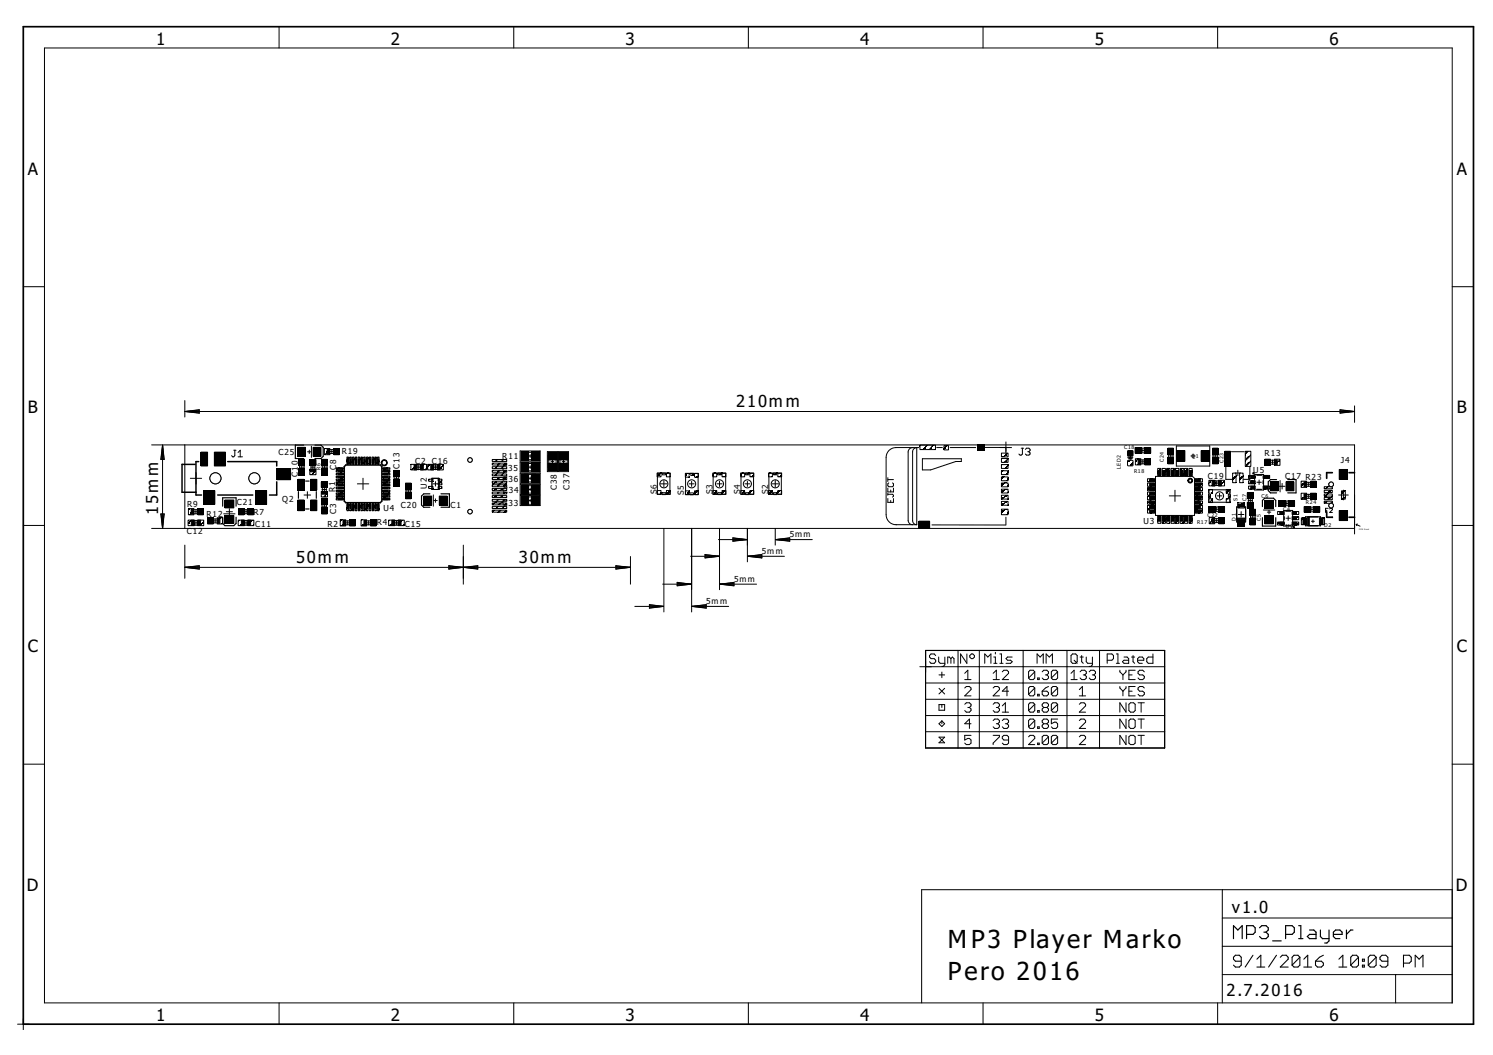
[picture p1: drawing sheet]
<svg xmlns="http://www.w3.org/2000/svg" width="297mm" height="210mm" viewBox="0 0 297 210" stroke-linecap="round" stroke-linejoin="round" font-family="sans-serif">
<defs><g id="words">
<g font-size="6">
<text x="188.6" y="188.6">MP3 Player Marko</text>
<text x="188.6" y="194.9">Pero 2016</text>
</g>
<g font-size="4.1">
<text x="31.1" y="8.9">1</text>
<text x="77.8" y="8.9">2</text>
<text x="124.4" y="8.9">3</text>
<text x="171.1" y="8.9">4</text>
<text x="217.8" y="8.9">5</text>
<text x="264.5" y="8.9">6</text>
<text x="5.5" y="34.7">A</text>
<text x="289.8" y="34.7">A</text>
<text x="5.5" y="82.2">B</text>
<text x="289.8" y="82.2">B</text>
<text x="5.5" y="129.7">C</text>
<text x="289.8" y="129.7">C</text>
<text x="5.4" y="177.2">D</text>
<text x="289.7" y="177.2">D</text>
<text x="31.1" y="203.1">1</text>
<text x="77.8" y="203.1">2</text>
<text x="124.4" y="203.1">3</text>
<text x="171.1" y="203.1">4</text>
<text x="217.8" y="203.1">5</text>
<text x="264.5" y="203.1">6</text>
</g>
<g font-size="4">
<text x="146.5" y="81">210mm</text>
<text x="31.5" y="102.4" transform="rotate(-90 31.5 102.4)">15mm</text>
<text x="58.9" y="112">50mm</text>
<text x="103.2" y="112">30mm</text>
<text x="245.1" y="181.6">v1.0</text>
<text x="244" y="198.2">2.7.2016</text>
</g>
<g font-size="2">
<text x="55.4" y="90.6">C25</text>
<text x="59.3" y="94.8" transform="rotate(-90 59.3 94.8)">C10</text>
<text x="66.8" y="93.6" transform="rotate(-90 66.8 93.6)">C8</text>
<text x="68" y="90.4">R19</text>
<text x="79.4" y="93.3" transform="rotate(-90 79.4 93.3)">C13</text>
<text x="82.6" y="92.2">C2 C16</text>
<text x="99.9" y="93.7">C35</text>
<text x="99.9" y="91.4">R11</text>
<text x="100" y="96">C36</text>
<text x="240.3" y="95.2">C19</text>
<text x="249.3" y="94">U5</text>
<text x="251.6" y="90.7">R13</text>
<text x="255.7" y="95.2">C17 R23</text>
<text x="266.8" y="92.1">J4</text>
<text x="37.2" y="100.9">R9</text>
<text x="47.1" y="100.5">C21</text>
<text x="56.1" y="99.9">Q2</text>
<text x="66.7" y="97.9" transform="rotate(-90 66.7 97.9)">R1</text>
<text x="76.3" y="101.6">U4</text>
<text x="79.7" y="101.1">C20</text>
<text x="84.9" y="97.3" transform="rotate(-90 84.9 97.3)">U2</text>
<text x="89.6" y="101.1">C1</text>
<text x="100" y="100.6">C33</text>
<text x="100" y="98.2">C34</text>
<text x="110.8" y="97.5" transform="rotate(-90 110.8 97.5)">C38</text>
<text x="113.3" y="97.4" transform="rotate(-90 113.3 97.4)">C37</text>
<text x="130.7" y="98.4" transform="rotate(-90 130.7 98.4)">S6</text>
<text x="136" y="98.6" transform="rotate(-90 136 98.6)">S5</text>
<text x="141.7" y="98.4" transform="rotate(-90 141.7 98.4)">S3</text>
<text x="147.3" y="98.4" transform="rotate(-90 147.3 98.4)">S4</text>
<text x="152.8" y="98.4" transform="rotate(-90 152.8 98.4)">S2</text>
<text x="37.2" y="106.3">C12</text>
<text x="41.1" y="102.9">R12</text>
<text x="50.4" y="102.5">R7</text>
<text x="50.7" y="104.8">C11</text>
<text x="65.2" y="104.8">R2</text>
<text x="66.9" y="102.2" transform="rotate(-90 66.9 102.2)">C3</text>
<text x="75" y="104.4">R4</text>
<text x="80.6" y="104.8">C15</text>
<text x="157.1" y="106.9">5mm</text>
<text x="227.5" y="104.3">U3</text>
<text x="151.6" y="110.2">5mm</text>
<text x="146" y="115.7">5mm</text>
<text x="140.5" y="120.2">5mm</text>
</g>
<g font-size="1.3">
<text x="223.7" y="89.4">C18</text>
<text x="63.8" y="93.6" transform="rotate(-90 63.8 93.6)">R6</text>
<text x="223" y="93.3" transform="rotate(-90 223 93.3)">LED2</text>
<text x="225.6" y="94.2">R18</text>
<text x="231.5" y="92" transform="rotate(-90 231.5 92)">C24</text>
<text x="237" y="91.1">Q1</text>
<text x="243.4" y="92.2" transform="rotate(-90 243.4 92.2)">C23</text>
<text x="246.2" y="99.6" transform="rotate(-90 246.2 99.6)">S1</text>
<text x="248" y="99.7" transform="rotate(-90 248 99.7)">C7</text>
<text x="251" y="99.1">C6</text>
<text x="255.3" y="101.7">C4</text>
<text x="259.8" y="100.4">R24</text>
<text x="238.2" y="104.3">R17</text>
<text x="240.3" y="102.8">C22</text>
<text x="245.9" y="103.6" transform="rotate(-90 245.9 103.6)">D1</text>
<text x="250.9" y="103.6" transform="rotate(-90 250.9 103.6)">C5</text>
<text x="255.8" y="105">U1</text>
<text x="263.4" y="104.8">D2</text>
</g>
<text font-size=".5" x="270.4" y="105.4">PCB Front</text>
</g></defs>
<g fill="#000" stroke="#000" stroke-width=".2">
<path d="M40 90h1.3v2.7h-1.3zM40.5 97.6h2.2v2.8h-2.2zM42.7 90h2.2v2.7h-2.2zM44.7 99.5h1.8v1.5h-1.8zM50.8 97.6h2.2v2.8h-2.2zM55.1 93.2h2.7v2.2h-2.7zM59.2 89h1.6v1.8h-1.6zM59.3 95.4h1.2v2.1h-1.2zM59.3 99.5h1.2v2.1h-1.2zM59.5 91.4h1.1v1.2h-1.1zM59.5 93.3h1.1v1.2h-1.1zM59.5 92h1.1v.6h-1.1z"/>
<path d="M59.5 93.3h1.1v.6h-1.1zM61.6 91.5h1.3v1.1h-1.3zM61.6 93.3h1.3v1.1h-1.3zM61.8 93.4h.9v.5h-.9zM61.8 92h.9v.5h-.9zM61.8 99.5h1.2v2.1h-1.2zM61.8 95.4h1.2v2.1h-1.2zM62.3 89h1.6v1.8h-1.6zM63.9 95.9h1.3v1.1h-1.3zM63.9 97.8h1.3v1.1h-1.3zM64 99.1h1.1v1.3h-1.1zM64 99.8h1v.5h-1z"/>
<path d="M64 91.4h1.1v1.2h-1.1zM64 93.3h1.1v1.2h-1.1zM64.1 92h1v.6h-1zM64.1 93.3h1v.6h-1zM64.1 97.9h.9v.4h-.9zM64.1 96.4h.9v.5h-.9zM64.5 89.2h1.1v1.3h-1.1zM65.1 89.4h.5v.9h-.5zM66.4 89.2h1.1v1.3h-1.1zM66.5 89.4h.5v.9h-.5zM66.9 93.1h1.3v.3h-1.3zM66.9 93.6h1.3v.3h-1.3z"/>
<path d="M66.9 94.2h1.3v.3h-1.3zM66.9 94.7h1.3v.3h-1.3zM66.9 95.3h1.3v.3h-1.3zM66.9 95.8h1.3v.3h-1.3zM66.9 96.4h1.3v.3h-1.3zM66.9 96.9h1.3v.3h-1.3zM66.9 97.5h1.3v.3h-1.3zM66.9 98.1h1.3v.3h-1.3zM66.9 98.6h1.3v.3h-1.3zM66.9 99.2h1.3v.3h-1.3zM67.2 93.1h1.2v.2h-1.2zM67.2 93.7h1.2v.2h-1.2z"/>
<path d="M67.2 94.2h1.2v.2h-1.2zM67.2 94.8h1.2v.2h-1.2zM67.2 95.3h1.2v.2h-1.2zM67.2 95.9h1.2v.2h-1.2zM67.2 96.4h1.2v.2h-1.2zM67.2 97h1.2v.2h-1.2zM67.2 97.6h1.2v.2h-1.2zM67.2 98.1h1.2v.2h-1.2zM67.2 98.7h1.2v.2h-1.2zM67.2 99.2h1.2v.2h-1.2zM69 90.9h.3v1.3h-.3zM69.1 91.3h.2v1.1h-.2z"/>
<path d="M69.6 90.9h.3v1.3h-.3zM69.6 91.3h.2v1.1h-.2zM70.1 90.9h.3v1.3h-.3zM70.2 91.3h.2v1.1h-.2zM70.7 90.9h.3v1.3h-.3zM70.7 91.3h.3v1.1h-.3zM71.2 90.9h.3v1.3h-.3zM71.3 91.3h.2v1.1h-.2zM71.8 90.9h.3v1.3h-.3zM71.8 91.3h.3v1.1h-.3zM72.4 90.9h.3v1.3h-.3zM72.4 91.3h.2v1.1h-.2z"/>
<path d="M72.9 90.9h.3v1.3h-.3zM73 91.3h.2v1.1h-.2zM73.5 90.9h.3v1.3h-.3zM73.5 91.3h.2v1.1h-.2zM74 90.9h.3v1.3h-.3zM74.1 91.3h.2v1.1h-.2zM74.6 90.9h.3v1.3h-.3zM74.6 91.3h.2v1.1h-.2zM75.1 90.9h.3v1.3h-.3zM75.2 91.3h.2v1.1h-.2zM76.1 99.2h1.1v.2h-1.1zM76.1 98.7h1.1v.2h-1.1z"/>
<path d="M76.1 98.1h1.1v.2h-1.1zM76.1 97.6h1.1v.2h-1.1zM76.1 97h1.1v.2h-1.1zM76.1 96.4h1.1v.2h-1.1zM76.1 95.9h1.1v.2h-1.1zM76.1 95.3h1.1v.2h-1.1zM76.1 94.8h1.1v.2h-1.1zM76.1 94.2h1.1v.2h-1.1zM76.1 93.7h1.1v.2h-1.1zM76.1 93.1h1.1v.2h-1.1zM76.3 99.2h1.3v.3h-1.3zM76.3 98.6h1.3v.3h-1.3z"/>
<path d="M76.3 98.1h1.3v.3h-1.3zM76.3 97.5h1.3v.3h-1.3zM76.3 96.9h1.3v.3h-1.3zM76.3 96.4h1.3v.3h-1.3zM76.3 95.8h1.3v.3h-1.3zM76.3 95.3h1.3v.3h-1.3zM76.3 94.7h1.3v.3h-1.3zM76.3 94.2h1.3v.3h-1.3zM76.3 93.6h1.3v.3h-1.3zM76.3 93.1h1.3v.3h-1.3zM78.3 95.5h1.1v1.2h-1.1zM78.3 93.6h1.1v1.2h-1.1z"/>
<path d="M78.3 95.5h1.1v.6h-1.1zM78.3 94.2h1.1v.6h-1.1zM80.7 96.1h1.1v1.2h-1.1zM80.7 98h1.1v1.2h-1.1zM80.7 96.8h1.1v.5h-1.1zM80.7 98h1.1v.6h-1.1zM81.7 92.4h1.3v1.1h-1.3zM82.4 92.4h.5v1.1h-.5zM83.6 92.4h1.3v1.1h-1.3zM83.7 92.4h.5v1.1h-.5zM84.3 98.7h1.6v1.8h-1.6zM85.1 92.4h1.2v1.1h-1.2z"/>
<path d="M85.3 96.8h.8v.4h-.8zM85.3 95.3h.8v.5h-.8zM85.7 92.4h.6v1.1h-.6zM87 92.4h1.2v1.1h-1.2zM87 92.4h.5v1.1h-.5zM87.2 96.8h.7v.4h-.7zM87.2 96.1h.7v.4h-.7zM87.2 95.3h.7v.4h-.7zM87.4 98.7h1.6v1.8h-1.6zM97.9 91.4h2.9v.4h-2.9zM97.9 92.1h2.9v.4h-2.9zM97.9 92.9h2.9v.3h-2.9z"/>
<path d="M97.9 93.6h2.9v.4h-2.9zM97.9 94.3h2.9v.4h-2.9zM97.9 95h2.9v.4h-2.9zM97.9 95.7h2.9v.4h-2.9zM97.9 96.5h2.9v.3h-2.9zM97.9 97.2h2.9v.4h-2.9zM97.9 97.9h2.9v.4h-2.9zM97.9 98.6h2.9v.4h-2.9zM97.9 99.4h2.9v.3h-2.9zM103.7 98.8h1.4v1.6h-1.4zM103.7 96.6h1.4v1.6h-1.4zM103.7 92.1h1.4v1.7h-1.4z"/>
<path d="M103.7 94.3h1.4v1.7h-1.4zM103.7 89.9h1.4v1.6h-1.4zM104.2 96.6h.9v1.6h-.9zM104.3 98.8h.8v1.6h-.8zM104.3 92.1h.8v1.6h-.8zM104.3 94.4h.8v1.6h-.8zM104.3 89.9h.8v1.6h-.8zM105.8 98.8h1.5v1.6h-1.5zM105.8 96.6h1.5v1.6h-1.5zM105.8 92.1h1.5v1.7h-1.5zM105.8 94.3h1.5v1.7h-1.5zM105.8 89.9h1.5v1.6h-1.5z"/>
<path d="M105.9 98.8h.8v1.6h-.8zM105.9 96.6h.8v1.6h-.8zM105.9 92.1h.8v1.6h-.8zM105.9 94.4h.8v1.6h-.8zM105.9 89.9h.8v1.6h-.8zM109.1 92.2h1.6v1.4h-1.6zM109.1 90.1h1.6v1.4h-1.6zM109.1 92.2h1.6v.8h-1.6zM109.1 90.6h1.6v.8h-1.6zM111.3 92.2h1.6v1.4h-1.6zM111.3 90.1h1.6v1.4h-1.6zM111.3 92.2h1.6v.8h-1.6z"/>
<path d="M111.3 90.6h1.6v.8h-1.6zM130.7 97.6h.8v.8h-.8zM130.7 94.1h.8v.8h-.8zM131.7 98h.8v.4h-.8zM131.7 94.1h.8v.4h-.8zM132.6 97.6h.7v.8h-.7zM132.6 94.1h.7v.8h-.7zM136.4 94.2h.7v.7h-.7zM136.4 97.7h.7v.7h-.7zM137.2 94.1h.8v.4h-.8zM137.2 98.1h.8v.3h-.8zM138.2 94.2h.7v.7h-.7z"/>
<path d="M138.2 97.7h.7v.7h-.7zM141.8 97.6h.8v.8h-.8zM141.8 94.1h.8v.8h-.8zM142.8 98h.7v.4h-.7zM142.8 94.1h.7v.4h-.7zM143.7 97.6h.7v.8h-.7zM143.7 94.1h.7v.8h-.7zM147.4 97.6h.7v.8h-.7zM147.4 94.1h.7v.8h-.7zM148.3 98h.8v.4h-.8zM148.3 94.1h.8v.4h-.8zM149.2 97.6h.8v.8h-.8z"/>
<path d="M149.2 94.1h.8v.8h-.8zM152.9 97.6h.8v.8h-.8zM152.9 94.1h.8v.8h-.8zM153.9 98h.7v.4h-.7zM153.9 94.1h.7v.4h-.7zM154.7 97.6h.8v.8h-.8zM154.7 94.1h.8v.8h-.8zM183 88.6h3.1v.9h-3.1zM187.8 88.7h.9v.8h-.9zM194.5 88.5h1.3v1.1h-1.3zM199.2 91.2h1.4v.8h-1.4zM199.2 92.4h1.4v.8h-1.4z"/>
<path d="M199.2 93.7h1.4v.7h-1.4zM199.2 94.9h1.4v.8h-1.4zM199.2 96.1h1.4v.8h-1.4zM199.2 97.3h1.4v.8h-1.4zM199.2 98.5h1.4v.8h-1.4zM199.2 99.8h1.4v.7h-1.4zM199.2 90.1h1.4v.8h-1.4zM225.8 89.1h1.3v1.1h-1.3zM225.9 91.3h1.1v1.2h-1.1zM226.4 91.4h.5v1h-.5zM226.5 89.1h.5v1h-.5zM227.7 89.1h1.2v1.1h-1.2z"/>
<path d="M227.8 89.1h.5v1h-.5zM227.8 91.3h1.1v1.2h-1.1zM227.9 91.4h.4v1h-.4zM228.3 95.2h1.4v.7h-1.4zM228.3 96.1h1.4v.7h-1.4zM228.3 97h1.4v.6h-1.4zM228.3 97.9h1.4v.6h-1.4zM228.3 98.8h1.4v.6h-1.4zM228.3 99.7h1.4v.6h-1.4zM228.7 95.3h1.1v.5h-1.1zM228.7 96.2h1.1v.5h-1.1zM228.7 97.1h1.1v.5h-1.1z"/>
<path d="M228.7 98h1.1v.5h-1.1zM228.7 98.8h1.1v.6h-1.1zM228.7 99.7h1.1v.5h-1.1zM230.3 93.2h.7v1.4h-.7zM230.4 93.6h.5v1.1h-.5zM231.2 93.2h.7v1.4h-.7zM231.3 93.6h.5v1.1h-.5zM232.1 93.2h.6v1.4h-.6zM232.2 93.6h.5v1.1h-.5zM232.4 89.2h1.1v1.2h-1.1zM232.4 91.1h1.1v1.2h-1.1zM232.4 89.8h1v.6h-1z"/>
<path d="M232.4 91.1h1v.6h-1zM233 93.2h.6v1.4h-.6zM233.1 93.6h.5v1.1h-.5zM233.9 93.2h.6v1.4h-.6zM234 93.6h.5v1.1h-.5zM234.1 89.7h1.6v2.1h-1.6zM234.8 93.2h.6v1.4h-.6zM234.8 93.6h.6v1.1h-.6zM235.7 93.2h.6v1.4h-.6zM235.7 93.6h.5v1.1h-.5zM236.6 93.2h.6v1.4h-.6zM236.6 93.6h.5v1.1h-.5z"/>
<path d="M237.7 99.7h1.1v.5h-1.1zM237.7 98.8h1.1v.6h-1.1zM237.7 98h1.1v.5h-1.1zM237.7 97.1h1.1v.5h-1.1zM237.7 96.2h1.1v.5h-1.1zM237.7 95.3h1.1v.5h-1.1zM237.8 99.7h1.4v.6h-1.4zM237.8 98.8h1.4v.6h-1.4zM237.8 97.9h1.4v.6h-1.4zM237.8 97h1.4v.6h-1.4zM237.8 96.1h1.4v.7h-1.4zM237.8 95.2h1.4v.7h-1.4z"/>
<path d="M239 89.7h1.6v2.1h-1.6zM240.5 98.3h.3v.7h-.3zM240.5 99.2h.7v.8h-.7zM240.5 97.4h.7v.7h-.7zM240.5 95.6h1.2v1.1h-1.2zM241.2 95.6h.5v1.1h-.5zM241.2 89.2h1.1v1.2h-1.1zM241.2 91.1h1.1v1.2h-1.1zM241.3 89.8h1v.6h-1zM241.3 91.1h1v.6h-1zM242.4 95.6h1.2v1.1h-1.2zM242.4 95.6h.6v1.1h-.6z"/>
<path d="M243.7 89.8h1.1v3h-1.1zM244 97.4h.7v.7h-.7zM244 99.2h.7v.8h-.7zM244.4 98.3h.4v.7h-.4zM245.2 94.1h.7v1.9h-.7zM246.6 94.1h.7v1.9h-.7zM247.8 89.8h1.1v3h-1.1zM248.2 99.9h1.1v1.2h-1.1zM248.2 98h1.1v1.2h-1.1zM248.3 98.7h.9v.4h-.9zM248.4 94.6h1.3v.6h-1.3zM248.4 95.7h1.3v.5h-1.3z"/>
<path d="M248.4 96.7h1.3v.6h-1.3zM248.9 94.6h.7v.6h-.7zM248.9 95.7h.7v.5h-.7zM248.9 96.7h.7v.6h-.7zM251.3 96.7h1.3v.6h-1.3zM251.3 94.6h1.3v.6h-1.3zM251.5 96.7h.7v.6h-.7zM251.5 94.6h.7v.6h-.7zM251.6 99.6h1.8v1.5h-1.8zM251.7 91.4h1.1v1.2h-1.1zM252.2 91.5h.5v1h-.5zM252.8 95.9h1.5v1.7h-1.5z"/>
<path d="M253.6 91.4h1.1v1.2h-1.1zM253.6 91.5h.5v1h-.5zM254.4 99.6h1.3v1.1h-1.3zM255.1 99.6h.5v1.1h-.5zM255.9 95.9h1.5v1.7h-1.5zM256.3 99.6h1.3v1.1h-1.3zM256.4 99.6h.5v1.1h-.5zM258.9 95.7h1.1v1.3h-1.1zM258.9 98.1h1.1v1.3h-1.1zM259.4 95.9h.5v.9h-.5zM259.4 98.3h.5v.9h-.5zM260.8 95.7h1.1v1.3h-1.1z"/>
<path d="M260.8 98.1h1.1v1.3h-1.1zM260.8 95.9h.5v.9h-.5zM260.8 98.3h.5v.9h-.5zM263.5 98.3h1.6v.4h-1.6zM263.5 99h1.6v.4h-1.6zM263.5 99.7h1.6v.4h-1.6zM263.5 97.6h1.6v.4h-1.6zM263.5 96.8h1.6v.5h-1.6zM266.4 93.4h1.7v2h-1.7zM266.9 97.7h.8v1.6h-.8zM37.4 103.5h1.3v1.1h-1.3zM37.5 101.2h1.1v1.2h-1.1z"/>
<path d="M38 101.3h.5v1h-.5zM38.1 103.5h.5v1h-.5zM39.3 103.5h1.2v1.1h-1.2zM39.3 103.5h.6v1h-.6zM39.4 101.2h1.1v1.2h-1.1zM39.5 101.3h.4v1h-.4zM41.3 103h1.1v1.2h-1.1zM41.9 103.1h.4v1h-.4zM43.2 103h1.1v1.2h-1.1zM43.3 103.1h.5v1h-.5zM44.7 102.6h1.8v1.5h-1.8zM47.4 103.5h1.2v1.1h-1.2z"/>
<path d="M47.5 101.2h1.1v1.2h-1.1zM48 103.5h.6v1h-.6zM48 101.3h.5v1h-.5zM49.3 103.5h1.2v1.1h-1.2zM49.3 103.5h.6v1h-.6zM49.3 101.2h1.1v1.2h-1.1zM49.4 101.3h.5v1h-.5zM64 101h1.1v1.3h-1.1zM64 101.1h1v.5h-1zM67.7 103.4h1.1v1.2h-1.1zM68.2 103.5h.5v1h-.5zM69 100.4h.3v1.2h-.3z"/>
<path d="M69.1 100.1h.2v1.1h-.2zM69.6 103.4h1.1v1.2h-1.1zM69.6 100.4h.3v1.2h-.3zM69.6 100.1h.2v1.1h-.2zM69.7 103.5h.4v1h-.4zM70.1 100.4h.3v1.2h-.3zM70.2 100.1h.2v1.1h-.2zM70.7 100.4h.3v1.2h-.3zM70.7 100.1h.3v1.1h-.3zM71.2 100.4h.3v1.2h-.3zM71.3 100.1h.2v1.1h-.2zM71.8 100.4h.3v1.2h-.3z"/>
<path d="M71.8 103.4h1.1v1.2h-1.1zM71.8 100.1h.3v1.1h-.3zM72.4 100.4h.3v1.2h-.3zM72.4 103.5h.5v1h-.5zM72.4 100.1h.2v1.1h-.2zM72.9 100.4h.3v1.2h-.3zM73 100.1h.2v1.1h-.2zM73.5 100.4h.3v1.2h-.3zM73.5 100.1h.2v1.1h-.2zM73.7 103.4h1.1v1.2h-1.1zM73.8 103.5h.5v1h-.5zM74 100.4h.3v1.2h-.3z"/>
<path d="M74.1 100.1h.2v1.1h-.2zM74.6 100.4h.3v1.2h-.3zM74.6 100.1h.2v1.1h-.2zM75.1 100.4h.3v1.2h-.3zM75.2 100.1h.2v1.1h-.2zM77.3 103.5h1.2v1.1h-1.2zM78 103.5h.5v1h-.5zM79.2 103.5h1.2v1.1h-1.2zM79.2 103.5h.6v1h-.6zM97.9 100.1h2.9v.4h-2.9zM97.9 100.8h2.9v.4h-2.9zM97.9 101.5h2.9v.4h-2.9z"/>
<path d="M182.8 103.7h2.2v1.4h-2.2zM199.2 101.3h1.4v1.1h-1.4zM228.3 100.6h1.4v.6h-1.4zM228.3 101.5h1.4v.6h-1.4zM228.7 100.6h1.1v.5h-1.1zM228.7 101.5h1.1v.5h-1.1zM230.3 102.7h.7v1.4h-.7zM230.4 102.6h.5v1.1h-.5zM231.2 102.7h.7v1.4h-.7zM231.3 102.6h.5v1.1h-.5zM232.1 102.7h.6v1.4h-.6zM232.2 102.6h.5v1.1h-.5z"/>
<path d="M233 102.7h.6v1.4h-.6zM233.1 102.6h.5v1.1h-.5zM233.9 102.7h.6v1.4h-.6zM234 102.6h.5v1.1h-.5zM234.8 102.7h.6v1.4h-.6zM234.8 102.6h.6v1.1h-.6zM235.7 102.7h.6v1.4h-.6zM235.7 102.6h.5v1.1h-.5zM236.6 102.7h.6v1.4h-.6zM236.6 102.6h.5v1.1h-.5zM237.7 101.5h1.1v.5h-1.1zM237.7 100.6h1.1v.5h-1.1z"/>
<path d="M237.8 101.5h1.4v.6h-1.4zM237.8 100.6h1.4v.6h-1.4zM240.5 100.8h1.2v1.1h-1.2zM240.6 103h1.1v1.2h-1.1zM241.1 103.1h.5v1h-.5zM241.2 100.8h.5v1.1h-.5zM242.4 100.8h1.2v1.1h-1.2zM242.4 100.8h.6v1.1h-.6zM242.5 103h1.1v1.2h-1.1zM242.5 103.1h.5v1h-.5zM246 103.1h1.8v.3h-1.8zM246.3 100.1h1.3v1h-1.3z"/>
<path d="M246.3 103.7h1.3v1h-1.3zM246.3 103.9h1.2v.5h-1.2zM246.3 100.4h1.2v.4h-1.2zM248.3 100.1h.9v.3h-.9zM248.7 101.3h1.1v1.3h-1.1zM248.7 103.2h1.1v1.2h-1.1zM248.7 102h1.1v.5h-1.1zM248.7 103.3h1.1v.5h-1.1zM251.6 102.7h1.8v1.5h-1.8zM254.2 101.8h1.3v.6h-1.3zM254.2 103.9h1.3v.6h-1.3zM254.6 101.8h.7v.5h-.7z"/>
<path d="M254.6 103.9h.7v.5h-.7zM257.1 103.9h1.3v.6h-1.3zM257.1 102.8h1.3v.6h-1.3zM257.1 101.8h1.3v.6h-1.3zM257.2 103.9h.7v.5h-.7zM257.2 102.8h.7v.6h-.7zM257.2 101.8h.7v.5h-.7zM258.9 103h1v1.4h-1zM259.2 103.1h.5v1.2h-.5zM259.5 100.8h1.2v1.1h-1.2zM260.1 100.8h.5v1.1h-.5zM260.2 102.8h.3v1.8h-.3z"/>
<path d="M261.3 100.8h1.3v1.1h-1.3zM261.4 100.8h.5v1.1h-.5zM262.5 103h1v1.4h-1zM262.8 103.1h.4v1.2h-.4zM266.4 101.6h1.7v2h-1.7z"/>
</g>
<g fill="#000" stroke="#000" stroke-width=".2">
<path d="M76 91.7a.61 .61 0 0 1 1 .1 .61 .61 0 0 1-.4 .9 .61 .61 0 0 1-.8-.6h.2a.47 .47 0 0 1 .7-.4 .47 .47 0 0 1 .1 .8 .47 .47 0 0 1-.8-.3v-.1h-.2z" fill-rule="evenodd"/>
<path d="M224.4 89.7h1v1h-1z" fill-rule="evenodd"/>
<path d="M224.4 91.6h1v1h-1z" fill-rule="evenodd"/>
<path d="M236.5 95.2a.48 .48 0 0 1 .7 .2 .48 .48 0 0 1-.3 .7 .48 .48 0 0 1-.6-.5h.2a.32 .32 0 0 1 .4-.2 .32 .32 0 0 1 .1 .5 .32 .32 0 0 1-.5-.1l-.2-.2z" fill-rule="evenodd"/>
<circle cx="249.4" cy="94.2" r=".15"/>
<circle cx="257.4" cy="104.9" r=".15"/>
</g>
<g fill="none" stroke="#000" stroke-width=".23">
<path d="M59.4 97.8v1.3M60.4 88.6h-1.6v2.6h1.6M60.8 95.7h.7M62.7 88.6h1.2l.4 .4v1.8l-.4 .4h-1.2M62.9 97.8v1.3M85.5 98.3h-1.2l-.4 .4v1.8l.4 .4h1.2M87.7 98.3h1.7v2.6h-1.7M224.4 91h1M224.6 91.3l.3-.3 .2 .3M250 97.4h1M250 94.6h1M251.3 95.7v.5"/>
<path d="M254 95.4h-1.2l-.5 .5v1.7l.5 .5h1.2M256.2 95.4h1.7v2.7h-1.7M44.3 102.9v1.2l.4 .5h1.8l.5-.5v-1.2M44.3 100.7v-1.7h2.7v1.7M60.8 101.3h.7M246 100.9h1.8v2.9h-1.8zM251.2 100.8v-1.2l.4-.5h1.8l.4 .5v1.2M251.2 103v1.7h2.6v-1.7M255.5 102.8v.6M255.8 101.7h1M255.8 104.5h1M259.7 102.8h3v1.8h-3z"/>
</g>
<g fill="none" stroke="#000" stroke-width=".2">
<path d="M36.8 79.7v3.3M30.2 88.5h239.3v17.7M32.3 88.6v16.5M32.3 88.6l.4 2.8h-.7zM32.3 88.6l-.1 2.8M32.3 88.6l.2 2.8M32.3 88.6l-.3 2.8M32.3 88.6l.3 2.8M36.8 88.5v16.6M36.8 81.9h232.6M36.8 81.9l2.8-.4v.7zM36.8 81.9l2.8 .1"/>
<path d="M36.8 81.9l2.8 .2M37.9 95.2h2.2M39 94v2.3M39.6 81.7l-2.8 .2M39.6 81.6l-2.8 .3M46.5 89.6h.4M46.7 89.6v1.1l-.2 .2h-.2l-.2-.2M47.4 90.9h.8M47.4 90l.4-.4v1.3M59.6 92.5v.8M59.6 92.9h.8M60 92.6v.7"/>
<path d="M60.5 98.5h1.3M60.5 92.5v.8M61.2 97.8v1.3M61.2 89.9h.7M61.5 89.6v.7M61.9 92.5v.9M61.9 92.9h.7M62 88.8v2.2M62.3 92.6v.7M62.7 92.5v.9M64.1 97.4h.9M64.1 92.9h1"/>
<path d="M64.1 92.5v.8M64.1 96.9v1M64.5 96.9v1M64.6 92.4v1.1M64.9 96.9v1M65.1 92.5v.8M65.6 90.2h.9M65.6 89.5h.9M65.6 89.9h.8M66 89.5v.7M71.1 96.3h2.3M72.2 95.1v2.3"/>
<path d="M78.4 94.8v.7M78.5 95.2h.8M78.9 94.8v.8M79.3 94.8v.7M80.7 97.7h1M80.8 97.3v.8M81.2 97.2v1M81.7 97.3v.8M82.8 92.9h1M82.9 92.5h.8M82.9 93.4h.8M83.3 92.4v1.1"/>
<path d="M85.9 95.2h1.4v2.2h-1.4zM86.1 92.9h1.1M86.2 96.3h.9M86.2 98.5v2.2M86.2 92.5h.8M86.2 93.4h.8M86.3 99.6h.7M86.6 92.4v1.1M86.6 95.8v.9M86.6 99.3v.6M103.5 89.7h4v2h-4zM103.5 91.9h4v2h-4z"/>
<path d="M103.5 94.2h4v2h-4zM103.5 96.4h4v2h-4zM103.5 98.6h4v2h-4zM105.1 94.4h.8M105.1 98.9h.8M105.1 98.1h.8M105.1 96.6h.8M105.1 92.2h.8M105.1 90h.8M105.1 93.7h.8M105.1 95.9h.8M105.1 91.5h.8"/>
<path d="M105.2 95.2h.5M105.2 97.4h.5M105.2 99.6h.5M105.2 92.9h.5M105.2 90.7h.5M105.5 90.4v.6M105.5 92.7v.5M105.5 94.9v.5M105.5 97.1v.6M105.5 99.3v.6M108.9 89.9h2v3.9h-2zM109.2 91.4v.9"/>
<path d="M109.6 91.8h.6M109.9 91.5v.6M110.6 91.4v.8M111.1 89.9h2v3.9h-2zM111.4 91.4v.9M111.8 91.8h.6M112.1 91.5v.6M112.9 91.4v.8M130.8 94.2h2.5v4.1h-2.5zM131.4 96.3h1.3M132.1 95.6v1.3M136.4 94.2h2.5v4.2h-2.5z"/>
<path d="M137.1 96.3h1M137.6 95.8v1M141.9 94.2h2.5v4.1h-2.5zM142.6 96.3h1.1M143.2 95.7v1.1M147.4 94.2h2.5v4.1h-2.5zM148.2 96.3h1M148.7 95.8v1M153 94.2h2.4v4.1h-2.4zM153.6 96.3h1.3M154.2 95.6v1.3M176.6 95.4h1.2"/>
<path d="M176.6 99.2v.7h1.2v-.7M176.6 98.3h1l.2 .2-.2 .4M176.6 95v.8M176.6 97.1v.8h1.2v-.8M176.6 98.1v.4M176.8 96.1l-.2 .2v.3l.2 .2h.8l.2-.2v-.3l-.2-.2M177.2 97.5v.4M177.2 99.6v.3M181.6 89l-.7 .3-.2 .6v13.6l.2 .6 .7 .3M181.8 89.3l.6-.3v15.4l-.6-.2-.2-.6v-13.7zM182.8 89h-4.6a1.95 1.95 0 0 0-1.9 2v11.4a1.99 1.99 0 0 0 2 2h4.1M183.5 91.3h7.8v.5h-1.1l-5 1.7h-1.7z"/>
<path d="M186.4 89h1.1M189 89h5.1M196 89h5.3M200.1 87.9v2.3M203.2 89.2h.4M203.4 89.2v1.1l-.2 .3-.5-.3M204 89.4l.2-.2h.5l.2 .2v.2l-.2 .3M204.5 89.9h.2M204.7 89.9l.2 .2v.2l-.2 .3h-.5l-.2-.3M224.5 91.2h.8M224.9 90.7v.9M226.9 92.3h1"/>
<path d="M226.9 91.5h1M227 90.1h.8M227 89.2h.8M227 89.6h.8M227 91.9h.8M227.4 89.2v.8M227.4 91.5v.8M229.9 94.8h7.4l.4 .4v7.4h-7.8zM232.5 90.3v.8M232.5 90.7h.8M232.6 98.7h2.3M232.9 90.3v.8"/>
<path d="M233.4 90.3v.8M233.8 97.5v2.3M234 88.7h6.7v4h-6.7zM236.9 90.7h.9M237.4 90.3v.8M240.5 97.5h4.2v2.4h-4.2zM241.3 90.3v.8M241.3 90.7h1M241.7 96.6h.8M241.7 95.7h.8M241.7 96.1h.8M241.8 90.3v.9"/>
<path d="M242.1 95.7v.8M242.1 98.7h1M242.3 90.3v.8M242.6 98.2v.9M243.9 92.8v2.6h1.3M245 89.9h2.5M245.7 94.1h1.1M246.3 93.6v1M248.3 99.6h.9M248.4 98.8v1.6M248.7 92.8v2.6h-1.3M248.8 99.1v.9"/>
<path d="M249.2 98.8v1.6M249.6 94.4h1.8v3.1h-1.8zM250.1 95.9h.9M250.5 95.5v.9M252.7 91.6h.9M252.7 92.4h.9M252.7 92h.9M253.2 91.5v.9M254.5 96.8h1.2M254.7 95.6v2.3M255.1 96.2v1.1M255.6 99.7h.8"/>
<path d="M256 99.8v.7M259.9 98.4h.9M259.9 96h.9M259.9 96.8h.9M259.9 99.1h.9M259.9 98.7h.9M260 96.4h.8M260.4 95.9v.9M260.4 98.3v.9M266.3 98.5h1.9M266.6 81.5l2.8 .4-2.8 .3zM266.6 81.7l2.8 .2"/>
<path d="M266.6 81.6l2.8 .3M267.3 97.5v2M269.4 81.9l-2.8 .1M269.4 81.9l-2.8 .2M269.5 80.8v3.2M30.2 105.1h239.3M32 102.3h.7l-.4 2.8zM32 102.3l.3 2.8M32.2 102.3l.1 2.8M32.5 102.3l-.2 2.8M32.6 102.3l-.3 2.8M36.8 108.5v6.6"/>
<path d="M36.8 112.9l2.8-.4v.7zM36.8 112.9h55.3M36.8 112.9l2.8 .1M36.8 112.9l2.8 .3M38.5 102.2h1M38.5 101.4h1M38.6 101.8h.8M38.6 103.5h.8M38.6 104.5h.8M38.6 104h.8M39 101.4v.8M39 103.6v.8"/>
<path d="M39.6 112.8l-2.8 .1M39.6 112.6l-2.8 .3M42.3 103.3h1M42.3 104h1M42.4 103.6h.8M42.8 103.3v.7M44.5 102.2h2.3M45 101.8h1.2M45.6 101.2v1.2M48.5 102.2h.9M48.5 101.4h.9M48.6 103.5h.8"/>
<path d="M48.6 104.5h.8M48.6 101.8h.7M48.6 104h.7M49 101.4v.8M49 103.7v.7M64.1 100.3v.8M64.1 100.7h.8M64.5 100.3v.8M65 100.3v.8M68.7 104.4h1M68.7 103.6h1M68.8 104h.8"/>
<path d="M69.2 103.7v.7M72.9 104.4h.9M72.9 103.6h.9M72.9 104h.9M73.3 103.6v.8M78.5 103.5h.8M78.5 104.5h.8M78.5 104h.8M78.9 103.7v.7M89.3 112.5l2.8 .4-2.8 .3zM89.3 112.8l2.8 .1M89.3 112.6l2.8 .3"/>
<path d="M92.1 112.9l-2.8 .1M92.1 112.9l-2.8 .3M92.2 108.5v7.7M92.2 112.9h33.1M92.2 112.9l2.9-.4v.7zM92.2 112.9l2.9 .1M92.2 112.9l2.9 .3M95.1 112.6l-2.9 .3M95.1 112.8l-2.9 .1M105.1 100.3h.8M122.5 112.5l2.8 .4-2.8 .3zM122.5 112.8l2.8 .1"/>
<path d="M122.5 112.6l2.8 .3M125.3 112.9l-2.8 .1M125.3 112.9l-2.8 .3M125.4 110.7v5.5M131.8 116.2h5.7M132.1 105.1v16.7M134.7 115.9l2.8 .3-2.8 .4zM134.7 116.1l2.8 .1M134.7 115.9l2.8 .3M137.4 110.7h5.7M137.5 116.2l-2.8 .2M137.5 116.2l-2.8 .3"/>
<path d="M137.6 105.1v16.7M140.3 110.3l2.8 .4-2.8 .3zM140.3 110.5l2.8 .2M140.3 110.4l2.8 .3M142.9 107.4h5.7M143.1 110.7l-2.8 .1M143.1 110.7l-2.8 .3M143.2 105.1v12.2M143.2 116.2h7.3M143.2 116.2l2.8-.3v.7zM143.2 116.2l2.8 .2M143.2 116.2l2.8 .3"/>
<path d="M145.8 107l2.8 .4-2.8 .3zM145.8 107.2l2.8 .2M145.8 107.1l2.8 .3M146 116.1l-2.8 .1M146 115.9l-2.8 .3M148.6 107.4l-2.8 .1M148.6 107.4l-2.8 .2M148.7 105.1v6.7M148.8 110.7h7.3M148.8 110.7l2.8-.4v.7zM148.8 110.7l2.8 .1M148.8 110.7l2.8 .3"/>
<path d="M151.6 110.5l-2.8 .2M151.6 110.4l-2.8 .3M154.2 105.1v3.4M154.3 107.4h7.3M154.3 107.4l2.8-.4v.7zM154.3 107.4l2.8 .1M154.3 107.4l2.8 .2M157.1 107.2l-2.8 .2M157.1 107.1l-2.8 .3M185.4 104.4l14.7 .1M200.1 102.9v1.5M241.6 103.2h.9"/>
<path d="M241.6 104h.9M241.7 100.9h.8M241.7 101.8h.8M241.7 103.6h.7M241.7 101.3h.7M242.1 101v.7M242.1 103.2v.8M246.4 102.4h1.1M246.9 101.8v1.1M248.8 102.5v.8M248.8 102.9h.9M249.2 102.4v.9"/>
<path d="M249.7 102.5v.8M251.4 101.5h2.2M252.1 101.9h.7M252.5 101.5v.8M255.4 101.6h1.8v3.1h-1.8zM255.6 100.6h.8M255.6 100.2h.8M255.8 103.1h.9M256.3 102.7v.8M260.6 101.8h.8M260.6 100.9h.8M260.7 101.3h.6"/>
<path d="M260.9 103.7h.6M261 101.1v.5M261.2 103.4v.6M263.7 101.5h.3M264.2 101.1h-.5v.9M264.5 101.3l.2-.2 .4 .2-.6 .7h.6M269.8 104.4l.8 .3M269.8 104.4l.1 .2M270 104.2l-.2 .2M126.3 120.6h5.7M129.2 120.3l2.8 .3-2.8 .4zM129.2 120.5l2.8 .1"/>
<path d="M129.2 120.4l2.8 .2M132 120.6l-2.8 .2M132 120.6l-2.8 .3M137.7 120.6h7.3M137.7 120.6l2.8-.3v.7zM137.7 120.6l2.8 .2M137.7 120.6l2.8 .3M140.5 120.5l-2.8 .1M140.5 120.4l-2.8 .2M183 132.7h2.3M184.1 131.5v2.3M3.5 203.8h2.3"/>
<path d="M4.6 202.6v2.3"/>
<circle cx="42.9" cy="95.2" r="1.1"/>
<circle cx="132.1" cy="96.3" r=".8"/>
<circle cx="137.6" cy="96.3" r=".8"/>
<circle cx="143.2" cy="96.3" r=".8"/>
<circle cx="148.7" cy="96.3" r=".8"/>
<circle cx="154.2" cy="96.3" r=".8"/>
<circle cx="242.6" cy="98.7" r=".8"/>
</g>
<path d="M38.8 92.4h-2.6v5.5h2.8M39.5 91.8h-.5v6.7h1.1M43.3 98.5h7M45.3 91.8h9.8v.9M55.1 95.9v2.6h-1.5M68.8 92.5h6.9l.3 .3v6.9l-.3 .3h-6.9l-.3-.3v-6.9z" fill="none" stroke="#000" stroke-width=".3"/>
<path d="M265.1 94h-1.2v1.2M268.4 94h1.1M263.9 101.8l.1 1.1h1.1M265.1 102.9h.1M268.4 102.9h1.1" fill="none" stroke="#000" stroke-width=".34"/>
<circle cx="42.9" cy="95.2" r="1.1" fill="#fff" stroke="#000" stroke-width=".2"/>
<circle cx="50.6" cy="95.2" r="1.1" fill="none" stroke="#000" stroke-width=".2"/>
<circle cx="50.6" cy="95.2" r="1.1" fill="#fff" stroke="#000" stroke-width=".2"/>
<circle cx="93.5" cy="91.5" r=".44" fill="none" stroke="#000" stroke-width=".2"/>
<circle cx="93.5" cy="91.5" r=".44" fill="#fff" stroke="#000" stroke-width=".2"/>
<circle cx="93.5" cy="101.8" r=".44" fill="none" stroke="#000" stroke-width=".2"/>
<circle cx="93.5" cy="101.8" r=".44" fill="#fff" stroke="#000" stroke-width=".2"/>
<circle cx="264.8" cy="100.6" r=".47" fill="none" stroke="#000" stroke-width=".2"/>
<circle cx="264.8" cy="100.6" r=".47" fill="#fff" stroke="#000" stroke-width=".2"/>
<circle cx="264.8" cy="96.4" r=".47" fill="none" stroke="#000" stroke-width=".2"/>
<circle cx="264.8" cy="96.4" r=".47" fill="#fff" stroke="#000" stroke-width=".2"/>
<g fill="none" stroke="#000" stroke-width=".2">
<path d="M8.8 9.5h280.1v190h-280.1zM55.5 5.3v4.2M102.2 5.3v4.2M148.9 5.3v4.2M195.6 5.3v4.2M242.3 5.3v4.2M4.6 57h4.2M288.9 57h4.3M4.6 104.5h4.2M288.9 104.5h4.3M184.1 129.4v3.3h47.6M184.1 135.9h47.6"/>
<path d="M184.1 139.1h47.6M186.2 130.4l-.3-.3h-.7l-.3 .3v.3l.3 .3h.7l.3 .4v.3l-.3 .3h-.7l-.3-.3M186.8 130.7v1l.2 .3h1M186.8 134.3h1.1M186.8 136.9l1.1 1.2M187.4 133.7v1.1M187.9 136.9l-1.1 1.2M188 130.7v1.6l-.3 .3h-.3M189.2 131l-.3-.3h-.3v1.3M189.2 131v1M189.2 131l.3-.3 .3 .3v1M190.6 129.4v19.4"/>
<path d="M191.9 134l.7-.7v1.9M191.9 135.2h1.3M191.9 136.9l.4-.3h.6l.3 .3v.3l-1.3 1.3h1.3M192.4 130.1v1.9l-1.3-1.9v1.9M193.3 130.1h.2l.4 .3v.3l-.4 .3h-.2l-.4-.3v-.3zM194.8 129.4v19.4M195.9 132v-1.9l.6 .6 .6-.6v1.9M197.6 135.2h1.2M197.6 134l.6-.7v1.9M197.6 136.9l.3-.3h.6l.3 .3v.3l-1.2 1.3h1.2M197.7 132h.7M197.7 130.7h.3v1.3"/>
<path d="M198 129.8v.3M198.9 130.1h.3v1.9M198.9 132h.7M199.4 133.7l.3-.4h.6l.4 .4v.3l-1.3 1.2h1.3M200.7 137.5h-1.3l.9-.9v1.9M201.4 130.7h-1l-.2 .3 .2 .4h.7l.3 .3-.3 .3h-.9M203.6 129.4v19.4M205.9 133.7l-1.3 1.2M205.9 133.7v1.2l-.3 .3h-.7l-.3-.3M205.9 133.7l-.3-.4h-.7l-.3 .4v1.2M205.9 136.9l-.3-.3h-.7l-.3 .3v1.2M205.9 136.9v1.2l-.3 .4h-.7l-.3-.4"/>
<path d="M205.9 136.9l-1.3 1.2M206.3 132v-1.9l.6 .6 .7-.6v1.9M206.4 134.9h.4v.3h-.4zM206.4 138.1h.4v.4h-.4zM207.3 133.7l.4-.4h.6l.3 .4v.3l-.3 .3M207.3 137.5h1l.3 .3v.3l-.3 .4h-.6l-.4-.4zM208 134.3h.3M208.1 132v-1.9l.7 .6 .6-.6v1.9M208.3 134.3l.3 .3v.3l-.3 .3h-.6l-.4-.3M208.6 136.6l-.6 .3-.7 .6M210.4 133.7v1.2l-.3 .3h-.6l-.3-.3M210.4 133.7l-.3-.4h-.6l-.3 .4v1.2"/>
<path d="M210.4 136.9l-.3-.3h-.6l-.3 .3v1.2M210.4 136.9v1.2l-.3 .4h-.6l-.3-.4M210.4 133.7l-1.2 1.2M210.4 136.9l-1.2 1.2M212.3 129.4v19.4M213.1 135.2h1.2M213.1 134l.6-.7v1.9M213.4 130.1h.6l.3 .3v1.3l-.3 .3h-.6l-.3-.3v-1.3zM213.7 131.4l.6 .6M214.7 138.5h1.3M214.7 137.2l.6-.6v1.9M214.9 130.7h.6"/>
<path d="M214.9 133.7l.3-.4h.6l.3 .4v.3l-.3 .3M215.2 130.4v1.3l.3 .3M215.5 134.3h.3M215.8 134.3l.3 .3v.3l-.3 .3h-.6l-.3-.3M216.1 130.7v1l.3 .3h.9M216.7 133.7l.3-.4h.6l.4 .4v.3l-.4 .3M217.3 134.3h.3M217.3 130.7v1.6l-.3 .3h-.3M217.6 134.3l.4 .3v.3l-.4 .3h-.6l-.3-.3M218.8 129.4v19.4M220.3 131.4h.9l.3-.4v-.6l-.3-.3h-.9v1.9M222.1 130.1h.3v1.9"/>
<path d="M222.1 132h.6M222.8 133.3v.4l.6 .6M222.8 136.6v.3l.6 .6M223.4 134.3v.9M223.4 137.5v1M223.6 130.7h.6l.4 .3v1h-1l-.3-.3 .3-.3h1M224 139.8v1.9l-1.2-1.9v1.9M224 133.3v.4l-.6 .6M224 136.6v.3l-.6 .6M224.6 134.3h.6M224.6 137.5h.6M225.1 130.7h.6"/>
<path d="M225.4 130.4v1.3l.3 .3M225.8 133.3h-1.2v1.9h1.2M225.8 136.6h-1.2v1.9h1.2M226.3 131.4h1.3v-.4l-.3-.3h-.6l-.4 .3v.7l.4 .3h.6M226.4 139.8h1.3M227 139.8v1.9M227.7 133.7l-.3-.4h-.7l-.3 .4v.3l.3 .3h.7l.3 .3v.3l-.3 .3h-.7l-.3-.3M227.7 136.9l-.3-.3h-.7l-.3 .3v.3l.3 .3h.7l.3 .3v.3l-.3 .4h-.7l-.3-.4M229.4 130.1v1.9h-.9l-.3-.3v-.7l.3-.3h.9M231.7 129.4v19.4h-47.6M4.6 152h4.2M184.1 142.4h47.6"/>
<path d="M184.1 145.6h47.6M186.8 140.2h1.1v1.1h-1.1zM186.8 146.7h1.1l-1.1 1.1h1.1zM187.4 140.2v.6M187.4 143.4v.6M187.4 143.4l.5 .6-.5 .5-.6-.5zM191.9 140.1l.4-.3h.6l.3 .3v.3l-.3 .4M192.6 140.8h.3M192.9 140.8l.3 .3v.3l-.3 .3h-.6l-.4-.3M193.2 146.3h-1.3v.9l.7-.3h.3l.3 .3v.6l-.3 .3h-.6l-.4-.3M193.2 144h-1.3l1-.9v1.8M197.6 143.4l.3-.3h.6l.3 .3v.3l-.3 .3"/>
<path d="M197.6 140.1l.3-.3h.6l.3 .3v.3l-.3 .4M197.6 146.3h1.2v.3l-1.2 1.2v.3M198.2 140.8h.3M198.2 144h.3M198.5 144l.3 .3v.3l-.3 .3h-.6l-.3-.3M198.5 140.8l.3 .3v.3l-.3 .3h-.6l-.3-.3M199.4 143.4l.3-.3h.6l.4 .3v.3l-.4 .3M199.4 141.7h1.3M199.4 140.4l.6-.6v1.9M200 144h.3M200.3 144l.4 .3v.3l-.4 .3h-.6l-.3-.3M200.7 147.2h-1l-.3-.3v-.3l.3-.3h.6l.4 .3v1.2l-.4 .3h-.6l-.3-.3"/>
<path d="M204.6 146.6l.3-.3h.7l.3 .3v.3l-1.3 1.2h1.3M205.9 143.4v1.2l-.3 .3h-.7l-.3-.3M205.9 140.1l-.3-.3h-.7l-.3 .3v1.3M205.9 143.4l-.3-.3h-.7l-.3 .3v1.2M205.9 140.1v1.3l-.3 .3h-.7l-.3-.3M205.9 140.1l-1.3 1.3M205.9 143.4l-1.3 1.2M206.4 141.4h.4v.3h-.4zM206.4 144.6h.4v.3h-.4zM206.4 147.8h.4v.3h-.4zM207.7 140.8l-.4-.4v-.3l.4-.3h.6l.3 .3v.3l-.3 .4M207.7 140.8l-.4 .3v.3l.4 .3h.6l.3-.3v-.3l-.3-.3"/>
<path d="M207.7 144l-.4-.3v-.3l.4-.3h.6l.3 .3v.3l-.3 .3M207.7 144l-.4 .3v.3l.4 .3h.6l.3-.3v-.3l-.3-.3M207.7 140.8h.6M207.7 144h.6M208.6 146.6v1.2l-.3 .3h-.6l-.4-.3M208.6 146.6l-.3-.3h-.6l-.4 .3v1.2M208.6 146.6l-1.3 1.2M210.4 140.1l-.3-.3h-.6l-.3 .3v1.3M210.4 143.1h-1.2v.9l.6-.3h.3l.3 .3v.6l-.3 .3h-.6l-.3-.3M210.4 146.6l-.3-.3h-.6l-.3 .3v1.2M210.4 140.1v1.3l-.3 .3h-.6l-.3-.3M210.4 146.6v1.2l-.3 .3h-.6l-.3-.3"/>
<path d="M210.4 140.1l-1.2 1.3M210.4 146.6l-1.2 1.2M214.7 140.1l.4-.3h.6l.3 .3v.3l-1.3 1.3h1.3M214.7 143.4l.4-.3h.6l.3 .3v.3l-1.3 1.2h1.3M214.7 146.6l.4-.3h.6l.3 .3v.3l-1.3 1.2h1.3M224 143.1v1.8l-1.2-1.8v1.8M224 146.3v1.8l-1.2-1.8v1.8M224.6 143.4l.3-.3h.6l.3 .3v1.2l-.3 .3h-.6l-.3-.3zM224.6 140.1l.3-.3h.6l.3 .3v1.3l-.3 .3h-.6l-.3-.3zM224.6 146.6l.3-.3h.6l.3 .3v1.2l-.3 .3h-.6l-.3-.3zM226.4 143.1h1.3M226.4 146.3h1.3"/>
<path d="M227 143.1v1.8M227 146.3v1.8M288.9 152h4.3M243.2 177v22.5M288.9 177h-105.5v22.5M55.5 199.5v4.3M102.2 199.5v4.3M148.9 199.5v4.3M195.6 199.5v4.3M242.3 199.5v4.3M243.2 193.9h45.7M243.2 188.3h45.7"/>
<path d="M243.2 182.6h45.7M277.7 193.9v5.6"/>
</g>
<g fill="none" stroke="#000" stroke-width=".23">
<path d="M184.1 129.4h47.6v19.4h-47.6zM245.4 186.8v-2.6l.9 .8 .8-.8v2.6M248 185.9h1.3l.4-.4v-.9l-.4-.4h-1.3v2.6M250.6 184.6l.4-.4h.9l.4 .4v.4l-.4 .5M251.5 185.5h.4M251.9 185.5l.4 .4v.4l-.4 .5h-.9l-.4-.5M253.2 187.2h1.7M255.8 185.9h1.3l.4-.4v-.9l-.4-.4h-1.3v2.6M258.4 184.2h.4v2.6M258.4 186.8h.8M260.5 185h.9l.4 .5v1.3h-1.3l-.4-.5 .4-.4h1.3M262.7 185v1.3l.4 .5h1.3"/>
<path d="M264.4 185v2.2l-.4 .4h-.5M265.3 185.9h1.7v-.4l-.4-.5h-.9l-.4 .5v.8l.4 .5h.9M267.9 185v1.8M269.2 185h-.5l-.8 .9"/>
</g>
<g fill="none" stroke="#000" stroke-width=".21">
<path d="M247 191.2h-1.2l-.4-.4v-.3l.4-.4h.8l.4 .4v1.5l-.4 .4h-.8l-.4-.4M249.3 190.1l-1.6 2.3M250.1 192.4h1.5M250.1 190.8l.7-.7v2.3M254 190.1l-1.6 2.3M254.7 190.5l.4-.4h.8l.4 .4v.3l-1.6 1.6h1.6M258.6 190.5v1.5l-.4 .4h-.7l-.4-.4M258.6 190.5l-.4-.4h-.7l-.4 .4v1.5M258.6 190.5l-1.5 1.5M259.4 192.4h1.6M259.4 190.8l.8-.7v2.3M261.7 191.2h1.2l.4 .4v.4l-.4 .4h-.8l-.4-.4z"/>
<path d="M263.3 190.1l-.8 .4-.8 .7M266.4 192.4h1.5M266.4 190.8l.8-.7v2.3M270.3 190.5v1.5l-.4 .4h-.8l-.4-.4M270.3 190.5l-.4-.4h-.8l-.4 .4v1.5M270.3 190.5l-1.6 1.5M271.1 192h.3v.4h-.3zM271.1 190.8h.3v.4h-.3zM273.8 190.5v1.5l-.4 .4h-.8l-.4-.4M273.8 190.5l-.4-.4h-.8l-.4 .4v1.5M273.8 190.5l-1.6 1.5M276.1 191.2h-1.1l-.4-.4v-.3l.4-.4h.7l.4 .4v1.5l-.4 .4h-.7l-.4-.4"/>
<path d="M279.2 191.6h1.2l.4-.4v-.7l-.4-.4h-1.2v2.3M281.6 192.4v-2.3l.7 .7 .8-.7v2.3"/>
</g>
<path d="M4.6 5.3h288.6v198.5h-288.6z" fill="none" stroke="#000" stroke-width=".34"/>
<use href="#words"/>
</svg>
